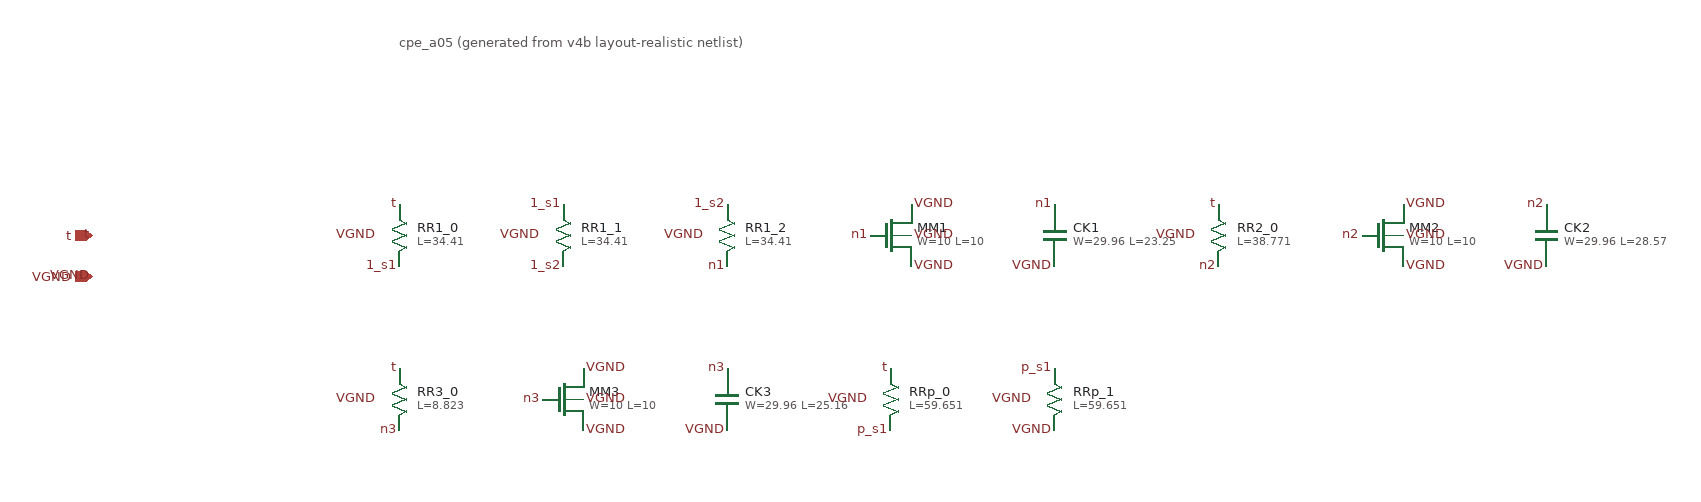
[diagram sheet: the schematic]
v {xschem version=3.4.8RC file_version=1.2}
G {}
K {}
V {}
S {}
E {}
T {cpe_a05  (generated from v4b layout-realistic netlist)} 0 -200 0 0 0.4 0.4 {}
C {iopin.sym} -300 0 0 0 {name=l1 sig_type=std_logic lab=t}
C {iopin.sym} -300 40 0 0 {name=l2 sig_type=std_logic lab=VGND}
C {lab_pin.sym} -300 0 0 0 {name=l3 sig_type=std_logic lab=t}
C {lab_pin.sym} -300 40 0 0 {name=l4 sig_type=std_logic lab=VGND}
C {sky130_fd_pr/res_xhigh_po_0p35.sym} 0 0 0 0 {name=RR1_0 L=34.41 model=res_xhigh_po_0p35 spiceprefix=X mult=1}
C {lab_pin.sym} 0 -30 0 0 {name=l5 sig_type=std_logic lab=t}
C {lab_pin.sym} 0 30 0 0 {name=l6 sig_type=std_logic lab=1_s1}
C {lab_pin.sym} -20 0 0 0 {name=l7 sig_type=std_logic lab=VGND}
C {sky130_fd_pr/res_xhigh_po_0p35.sym} 160 0 0 0 {name=RR1_1 L=34.41 model=res_xhigh_po_0p35 spiceprefix=X mult=1}
C {lab_pin.sym} 160 -30 0 0 {name=l8 sig_type=std_logic lab=1_s1}
C {lab_pin.sym} 160 30 0 0 {name=l9 sig_type=std_logic lab=1_s2}
C {lab_pin.sym} 140 0 0 0 {name=l10 sig_type=std_logic lab=VGND}
C {sky130_fd_pr/res_xhigh_po_0p35.sym} 320 0 0 0 {name=RR1_2 L=34.41 model=res_xhigh_po_0p35 spiceprefix=X mult=1}
C {lab_pin.sym} 320 -30 0 0 {name=l11 sig_type=std_logic lab=1_s2}
C {lab_pin.sym} 320 30 0 0 {name=l12 sig_type=std_logic lab=n1}
C {lab_pin.sym} 300 0 0 0 {name=l13 sig_type=std_logic lab=VGND}
C {sky130_fd_pr/nfet_01v8.sym} 480 0 0 0 {name=MM1 W=10 L=10 nf=1 mult=97 model=nfet_01v8 spiceprefix=X}
C {lab_pin.sym} 500 -30 0 1 {name=l14 sig_type=std_logic lab=VGND}
C {lab_pin.sym} 460 0 0 0 {name=l15 sig_type=std_logic lab=n1}
C {lab_pin.sym} 500 30 0 1 {name=l16 sig_type=std_logic lab=VGND}
C {lab_pin.sym} 500 0 0 1 {name=l17 sig_type=std_logic lab=VGND}
C {sky130_fd_pr/cap_mim_m3_1.sym} 640 0 0 0 {name=CK1 model=cap_mim_m3_1 W=29.96 L=23.25 MF=12 spiceprefix=X}
C {lab_pin.sym} 640 -30 0 0 {name=l18 sig_type=std_logic lab=n1}
C {lab_pin.sym} 640 30 0 0 {name=l19 sig_type=std_logic lab=VGND}
C {sky130_fd_pr/res_xhigh_po_0p35.sym} 800 0 0 0 {name=RR2_0 L=38.771 model=res_xhigh_po_0p35 spiceprefix=X mult=1}
C {lab_pin.sym} 800 -30 0 0 {name=l20 sig_type=std_logic lab=t}
C {lab_pin.sym} 800 30 0 0 {name=l21 sig_type=std_logic lab=n2}
C {lab_pin.sym} 780 0 0 0 {name=l22 sig_type=std_logic lab=VGND}
C {sky130_fd_pr/nfet_01v8.sym} 960 0 0 0 {name=MM2 W=10 L=10 nf=1 mult=83 model=nfet_01v8 spiceprefix=X}
C {lab_pin.sym} 980 -30 0 1 {name=l23 sig_type=std_logic lab=VGND}
C {lab_pin.sym} 940 0 0 0 {name=l24 sig_type=std_logic lab=n2}
C {lab_pin.sym} 980 30 0 1 {name=l25 sig_type=std_logic lab=VGND}
C {lab_pin.sym} 980 0 0 1 {name=l26 sig_type=std_logic lab=VGND}
C {sky130_fd_pr/cap_mim_m3_1.sym} 1120 0 0 0 {name=CK2 model=cap_mim_m3_1 W=29.96 L=28.57 MF=8 spiceprefix=X}
C {lab_pin.sym} 1120 -30 0 0 {name=l27 sig_type=std_logic lab=n2}
C {lab_pin.sym} 1120 30 0 0 {name=l28 sig_type=std_logic lab=VGND}
C {sky130_fd_pr/res_xhigh_po_0p35.sym} 0 160 0 0 {name=RR3_0 L=8.823 model=res_xhigh_po_0p35 spiceprefix=X mult=1}
C {lab_pin.sym} 0 130 0 0 {name=l29 sig_type=std_logic lab=t}
C {lab_pin.sym} 0 190 0 0 {name=l30 sig_type=std_logic lab=n3}
C {lab_pin.sym} -20 160 0 0 {name=l31 sig_type=std_logic lab=VGND}
C {sky130_fd_pr/nfet_01v8.sym} 160 160 0 0 {name=MM3 W=10 L=10 nf=1 mult=34 model=nfet_01v8 spiceprefix=X}
C {lab_pin.sym} 180 130 0 1 {name=l32 sig_type=std_logic lab=VGND}
C {lab_pin.sym} 140 160 0 0 {name=l33 sig_type=std_logic lab=n3}
C {lab_pin.sym} 180 190 0 1 {name=l34 sig_type=std_logic lab=VGND}
C {lab_pin.sym} 180 160 0 1 {name=l35 sig_type=std_logic lab=VGND}
C {sky130_fd_pr/cap_mim_m3_1.sym} 320 160 0 0 {name=CK3 model=cap_mim_m3_1 W=29.96 L=25.16 MF=4 spiceprefix=X}
C {lab_pin.sym} 320 130 0 0 {name=l36 sig_type=std_logic lab=n3}
C {lab_pin.sym} 320 190 0 0 {name=l37 sig_type=std_logic lab=VGND}
C {sky130_fd_pr/res_xhigh_po_0p35.sym} 480 160 0 0 {name=RRp_0 L=59.651 model=res_xhigh_po_0p35 spiceprefix=X mult=1}
C {lab_pin.sym} 480 130 0 0 {name=l38 sig_type=std_logic lab=t}
C {lab_pin.sym} 480 190 0 0 {name=l39 sig_type=std_logic lab=p_s1}
C {lab_pin.sym} 460 160 0 0 {name=l40 sig_type=std_logic lab=VGND}
C {sky130_fd_pr/res_xhigh_po_0p35.sym} 640 160 0 0 {name=RRp_1 L=59.651 model=res_xhigh_po_0p35 spiceprefix=X mult=1}
C {lab_pin.sym} 640 130 0 0 {name=l41 sig_type=std_logic lab=p_s1}
C {lab_pin.sym} 640 190 0 0 {name=l42 sig_type=std_logic lab=VGND}
C {lab_pin.sym} 620 160 0 0 {name=l43 sig_type=std_logic lab=VGND}
